VERSION 5.7 ;
  NOWIREEXTENSIONATPIN ON ;
  DIVIDERCHAR "/" ;
  BUSBITCHARS "[]" ;
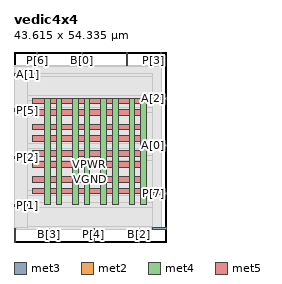
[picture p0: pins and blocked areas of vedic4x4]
MACRO vedic4x4
  CLASS BLOCK ;
  FOREIGN vedic4x4 ;
  ORIGIN 0.000 0.000 ;
  SIZE 43.615 BY 54.335 ;
  PIN A[0]
    DIRECTION INPUT ;
    USE SIGNAL ;
    ANTENNAGATEAREA 0.126000 ;
    PORT
      LAYER met3 ;
        RECT 39.615 27.240 43.615 27.840 ;
    END
  END A[0]
  PIN A[1]
    DIRECTION INPUT ;
    USE SIGNAL ;
    ANTENNAGATEAREA 0.213000 ;
    PORT
      LAYER met3 ;
        RECT 0.000 47.640 4.000 48.240 ;
    END
  END A[1]
  PIN A[2]
    DIRECTION INPUT ;
    USE SIGNAL ;
    ANTENNAGATEAREA 0.159000 ;
    PORT
      LAYER met3 ;
        RECT 39.615 40.840 43.615 41.440 ;
    END
  END A[2]
  PIN A[3]
    DIRECTION INPUT ;
    USE SIGNAL ;
    ANTENNAGATEAREA 0.126000 ;
    PORT
      LAYER met3 ;
        RECT 39.615 3.440 43.615 4.040 ;
    END
  END A[3]
  PIN B[0]
    DIRECTION INPUT ;
    USE SIGNAL ;
    ANTENNAGATEAREA 0.213000 ;
    PORT
      LAYER met2 ;
        RECT 19.410 50.335 19.690 54.335 ;
    END
  END B[0]
  PIN B[1]
    DIRECTION INPUT ;
    USE SIGNAL ;
    ANTENNAGATEAREA 0.159000 ;
    PORT
      LAYER met2 ;
        RECT 0.090 0.000 0.370 4.000 ;
    END
  END B[1]
  PIN B[2]
    DIRECTION INPUT ;
    USE SIGNAL ;
    ANTENNAGATEAREA 0.213000 ;
    PORT
      LAYER met2 ;
        RECT 35.510 0.000 35.790 4.000 ;
    END
  END B[2]
  PIN B[3]
    DIRECTION INPUT ;
    USE SIGNAL ;
    ANTENNAGATEAREA 0.126000 ;
    PORT
      LAYER met2 ;
        RECT 9.750 0.000 10.030 4.000 ;
    END
  END B[3]
  PIN P[0]
    DIRECTION OUTPUT TRISTATE ;
    USE SIGNAL ;
    ANTENNADIFFAREA 0.795200 ;
    PORT
      LAYER met2 ;
        RECT 32.290 50.335 32.570 54.335 ;
    END
  END P[0]
  PIN P[1]
    DIRECTION OUTPUT TRISTATE ;
    USE SIGNAL ;
    ANTENNADIFFAREA 0.795200 ;
    PORT
      LAYER met3 ;
        RECT 0.000 10.240 4.000 10.840 ;
    END
  END P[1]
  PIN P[2]
    DIRECTION OUTPUT TRISTATE ;
    USE SIGNAL ;
    ANTENNADIFFAREA 0.795200 ;
    PORT
      LAYER met3 ;
        RECT 0.000 23.840 4.000 24.440 ;
    END
  END P[2]
  PIN P[3]
    DIRECTION OUTPUT TRISTATE ;
    USE SIGNAL ;
    ANTENNADIFFAREA 0.795200 ;
    PORT
      LAYER met2 ;
        RECT 41.950 50.335 42.230 54.335 ;
    END
  END P[3]
  PIN P[4]
    DIRECTION OUTPUT TRISTATE ;
    USE SIGNAL ;
    ANTENNADIFFAREA 0.795200 ;
    PORT
      LAYER met2 ;
        RECT 22.630 0.000 22.910 4.000 ;
    END
  END P[4]
  PIN P[5]
    DIRECTION OUTPUT TRISTATE ;
    USE SIGNAL ;
    ANTENNADIFFAREA 0.795200 ;
    PORT
      LAYER met3 ;
        RECT 0.000 37.440 4.000 38.040 ;
    END
  END P[5]
  PIN P[6]
    DIRECTION OUTPUT TRISTATE ;
    USE SIGNAL ;
    ANTENNADIFFAREA 0.795200 ;
    PORT
      LAYER met2 ;
        RECT 6.530 50.335 6.810 54.335 ;
    END
  END P[6]
  PIN P[7]
    DIRECTION OUTPUT TRISTATE ;
    USE SIGNAL ;
    ANTENNADIFFAREA 0.445500 ;
    PORT
      LAYER met3 ;
        RECT 39.615 13.640 43.615 14.240 ;
    END
  END P[7]
  PIN VGND
    DIRECTION INOUT ;
    USE GROUND ;
    PORT
      LAYER met4 ;
        RECT 12.045 10.640 13.645 41.140 ;
    END
    PORT
      LAYER met4 ;
        RECT 20.095 10.640 21.695 41.140 ;
    END
    PORT
      LAYER met4 ;
        RECT 28.145 10.640 29.745 41.140 ;
    END
    PORT
      LAYER met4 ;
        RECT 36.195 10.640 37.795 41.140 ;
    END
    PORT
      LAYER met5 ;
        RECT 5.280 17.115 37.960 18.715 ;
    END
    PORT
      LAYER met5 ;
        RECT 5.280 24.590 37.960 26.190 ;
    END
    PORT
      LAYER met5 ;
        RECT 5.280 32.065 37.960 33.665 ;
    END
    PORT
      LAYER met5 ;
        RECT 5.280 39.540 37.960 41.140 ;
    END
  END VGND
  PIN VPWR
    DIRECTION INOUT ;
    USE POWER ;
    PORT
      LAYER met4 ;
        RECT 8.745 10.640 10.345 41.040 ;
    END
    PORT
      LAYER met4 ;
        RECT 16.795 10.640 18.395 41.040 ;
    END
    PORT
      LAYER met4 ;
        RECT 24.845 10.640 26.445 41.040 ;
    END
    PORT
      LAYER met4 ;
        RECT 32.895 10.640 34.495 41.040 ;
    END
    PORT
      LAYER met5 ;
        RECT 5.280 13.815 37.960 15.415 ;
    END
    PORT
      LAYER met5 ;
        RECT 5.280 21.290 37.960 22.890 ;
    END
    PORT
      LAYER met5 ;
        RECT 5.280 28.765 37.960 30.365 ;
    END
    PORT
      LAYER met5 ;
        RECT 5.280 36.240 37.960 37.840 ;
    END
  END VPWR
  OBS
      LAYER li1 ;
        RECT 5.520 10.795 37.720 40.885 ;
      LAYER met1 ;
        RECT 0.070 10.640 42.250 41.040 ;
      LAYER met2 ;
        RECT 0.100 50.055 6.250 50.335 ;
        RECT 7.090 50.055 19.130 50.335 ;
        RECT 19.970 50.055 32.010 50.335 ;
        RECT 32.850 50.055 41.670 50.335 ;
        RECT 0.100 4.280 42.220 50.055 ;
        RECT 0.650 3.555 9.470 4.280 ;
        RECT 10.310 3.555 22.350 4.280 ;
        RECT 23.190 3.555 35.230 4.280 ;
        RECT 36.070 3.555 42.220 4.280 ;
      LAYER met3 ;
        RECT 4.400 47.240 39.615 48.090 ;
        RECT 4.000 41.840 39.615 47.240 ;
        RECT 4.000 40.440 39.215 41.840 ;
        RECT 4.000 38.440 39.615 40.440 ;
        RECT 4.400 37.040 39.615 38.440 ;
        RECT 4.000 28.240 39.615 37.040 ;
        RECT 4.000 26.840 39.215 28.240 ;
        RECT 4.000 24.840 39.615 26.840 ;
        RECT 4.400 23.440 39.615 24.840 ;
        RECT 4.000 14.640 39.615 23.440 ;
        RECT 4.000 13.240 39.215 14.640 ;
        RECT 4.000 11.240 39.615 13.240 ;
        RECT 4.400 9.840 39.615 11.240 ;
        RECT 4.000 4.440 39.615 9.840 ;
        RECT 4.000 3.575 39.215 4.440 ;
  END
END vedic4x4
END LIBRARY

